VERSION 5.7 ;
  NOWIREEXTENSIONATPIN ON ;
  DIVIDERCHAR "/" ;
  BUSBITCHARS "[]" ;
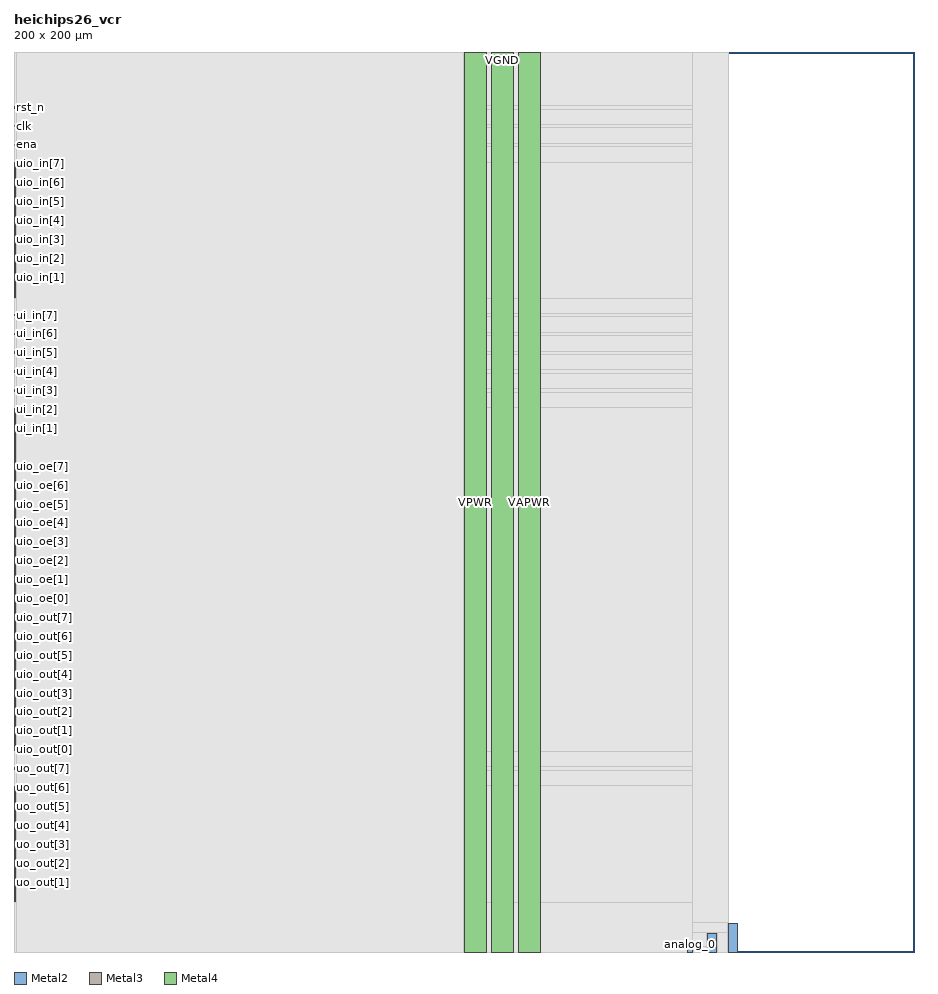
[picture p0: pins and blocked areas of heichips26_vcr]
MACRO heichips26_vcr
  CLASS BLOCK ;
  FOREIGN heichips26_vcr ;
  ORIGIN 0.000 0.000 ;
  SIZE 200.000 BY 200.000 ;
  PIN analog_0
    ANTENNADIFFAREA 86.099998 ;
    PORT
      LAYER Metal2 ;
        RECT 149.740 0.000 150.740 1.000 ;
    END
  END analog_0
  PIN analog_1
    ANTENNADIFFAREA 57.399998 ;
    PORT
      LAYER Metal2 ;
        RECT 154.040 0.000 156.040 4.170 ;
    END
  END analog_1
  PIN analog_2
    ANTENNADIFFAREA 57.399998 ;
    PORT
      LAYER Metal2 ;
        RECT 158.840 0.000 160.840 6.410 ;
    END
  END analog_2
  PIN clk
    PORT
      LAYER Metal3 ;
        RECT 0.000 183.340 0.400 183.740 ;
    END
  END clk
  PIN ena
    PORT
      LAYER Metal3 ;
        RECT 0.000 179.140 0.400 179.540 ;
    END
  END ena
  PIN rst_n
    PORT
      LAYER Metal3 ;
        RECT 0.000 187.540 0.400 187.940 ;
    END
  END rst_n
  PIN ui_in[0]
    ANTENNADIFFAREA 1.166200 ;
    PORT
      LAYER Metal3 ;
        RECT 0.000 44.740 0.400 120.740 ;
    END
  END ui_in[0]
  PIN ui_in[1]
    PORT
      LAYER Metal3 ;
        RECT 0.000 116.140 0.400 116.540 ;
    END
  END ui_in[1]
  PIN ui_in[2]
    PORT
      LAYER Metal3 ;
        RECT 0.000 120.340 0.400 120.740 ;
    END
  END ui_in[2]
  PIN ui_in[3]
    ANTENNAGATEAREA 9.900000 ;
    PORT
      LAYER Metal3 ;
        RECT 0.000 124.540 2.550 124.940 ;
    END
  END ui_in[3]
  PIN ui_in[4]
    ANTENNAGATEAREA 9.900000 ;
    PORT
      LAYER Metal3 ;
        RECT 0.000 128.740 0.400 129.140 ;
    END
  END ui_in[4]
  PIN ui_in[5]
    ANTENNAGATEAREA 9.900000 ;
    PORT
      LAYER Metal3 ;
        RECT 0.000 132.940 0.400 133.340 ;
    END
  END ui_in[5]
  PIN ui_in[6]
    ANTENNAGATEAREA 9.900000 ;
    PORT
      LAYER Metal3 ;
        RECT 0.000 137.140 0.400 137.540 ;
    END
  END ui_in[6]
  PIN ui_in[7]
    ANTENNAGATEAREA 9.900000 ;
    PORT
      LAYER Metal3 ;
        RECT 0.000 141.340 0.400 141.740 ;
    END
  END ui_in[7]
  PIN uio_in[0]
    ANTENNADIFFAREA 1.166200 ;
    PORT
      LAYER Metal3 ;
        RECT 0.000 145.540 0.400 175.340 ;
    END
  END uio_in[0]
  PIN uio_in[1]
    PORT
      LAYER Metal3 ;
        RECT 0.000 149.740 0.400 150.140 ;
    END
  END uio_in[1]
  PIN uio_in[2]
    PORT
      LAYER Metal3 ;
        RECT 0.000 153.940 0.400 154.340 ;
    END
  END uio_in[2]
  PIN uio_in[3]
    PORT
      LAYER Metal3 ;
        RECT 0.000 158.140 0.400 158.540 ;
    END
  END uio_in[3]
  PIN uio_in[4]
    PORT
      LAYER Metal3 ;
        RECT 0.000 162.340 0.400 162.740 ;
    END
  END uio_in[4]
  PIN uio_in[5]
    PORT
      LAYER Metal3 ;
        RECT 0.000 166.540 0.400 166.940 ;
    END
  END uio_in[5]
  PIN uio_in[6]
    PORT
      LAYER Metal3 ;
        RECT 0.000 170.740 0.400 171.140 ;
    END
  END uio_in[6]
  PIN uio_in[7]
    PORT
      LAYER Metal3 ;
        RECT 0.000 174.940 0.400 175.340 ;
    END
  END uio_in[7]
  PIN uio_oe[0]
    PORT
      LAYER Metal3 ;
        RECT 0.000 78.340 0.400 78.740 ;
    END
  END uio_oe[0]
  PIN uio_oe[1]
    PORT
      LAYER Metal3 ;
        RECT 0.000 82.540 0.400 82.940 ;
    END
  END uio_oe[1]
  PIN uio_oe[2]
    PORT
      LAYER Metal3 ;
        RECT 0.000 86.740 0.400 87.140 ;
    END
  END uio_oe[2]
  PIN uio_oe[3]
    PORT
      LAYER Metal3 ;
        RECT 0.000 90.940 0.400 91.340 ;
    END
  END uio_oe[3]
  PIN uio_oe[4]
    PORT
      LAYER Metal3 ;
        RECT 0.000 95.140 0.400 95.540 ;
    END
  END uio_oe[4]
  PIN uio_oe[5]
    PORT
      LAYER Metal3 ;
        RECT 0.000 99.340 0.400 99.740 ;
    END
  END uio_oe[5]
  PIN uio_oe[6]
    PORT
      LAYER Metal3 ;
        RECT 0.000 103.540 0.400 103.940 ;
    END
  END uio_oe[6]
  PIN uio_oe[7]
    PORT
      LAYER Metal3 ;
        RECT 0.000 107.740 0.400 108.140 ;
    END
  END uio_oe[7]
  PIN uio_out[0]
    PORT
      LAYER Metal3 ;
        RECT 0.000 44.740 0.400 45.140 ;
    END
  END uio_out[0]
  PIN uio_out[1]
    PORT
      LAYER Metal3 ;
        RECT 0.000 48.940 0.400 49.340 ;
    END
  END uio_out[1]
  PIN uio_out[2]
    PORT
      LAYER Metal3 ;
        RECT 0.000 53.140 0.400 53.540 ;
    END
  END uio_out[2]
  PIN uio_out[3]
    PORT
      LAYER Metal3 ;
        RECT 0.000 57.340 0.400 57.740 ;
    END
  END uio_out[3]
  PIN uio_out[4]
    PORT
      LAYER Metal3 ;
        RECT 0.000 61.540 0.400 61.940 ;
    END
  END uio_out[4]
  PIN uio_out[5]
    PORT
      LAYER Metal3 ;
        RECT 0.000 65.740 0.400 66.140 ;
    END
  END uio_out[5]
  PIN uio_out[6]
    PORT
      LAYER Metal3 ;
        RECT 0.000 69.940 0.400 70.340 ;
    END
  END uio_out[6]
  PIN uio_out[7]
    PORT
      LAYER Metal3 ;
        RECT 0.000 74.140 0.400 74.540 ;
    END
  END uio_out[7]
  PIN uo_out[0]
    ANTENNADIFFAREA 1.166200 ;
    PORT
      LAYER Metal3 ;
        RECT 0.000 11.140 0.400 36.740 ;
    END
  END uo_out[0]
  PIN uo_out[1]
    PORT
      LAYER Metal3 ;
        RECT 0.000 15.340 0.400 15.740 ;
    END
  END uo_out[1]
  PIN uo_out[2]
    PORT
      LAYER Metal3 ;
        RECT 0.000 19.540 0.400 19.940 ;
    END
  END uo_out[2]
  PIN uo_out[3]
    PORT
      LAYER Metal3 ;
        RECT 0.000 23.740 0.400 24.140 ;
    END
  END uo_out[3]
  PIN uo_out[4]
    PORT
      LAYER Metal3 ;
        RECT 0.000 27.940 0.400 28.340 ;
    END
  END uo_out[4]
  PIN uo_out[5]
    PORT
      LAYER Metal3 ;
        RECT 0.000 32.140 0.400 32.540 ;
    END
  END uo_out[5]
  PIN uo_out[6]
    PORT
      LAYER Metal3 ;
        RECT 0.000 36.340 0.400 36.740 ;
    END
  END uo_out[6]
  PIN uo_out[7]
    ANTENNADIFFAREA 9.880000 ;
    PORT
      LAYER Metal3 ;
        RECT 0.000 40.540 0.400 40.940 ;
    END
  END uo_out[7]
  PIN VAPWR
    USE POWER ;
    ANTENNADIFFAREA 987.272156 ;
    PORT
      LAYER Metal4 ;
        RECT 112.000 0.000 117.000 200.000 ;
    END
  END VAPWR
  PIN VGND
    USE GROUND ;
    ANTENNADIFFAREA 744.113403 ;
    PORT
      LAYER Metal4 ;
        RECT 106.000 0.000 111.000 200.000 ;
    END
  END VGND
  PIN VPWR
    USE POWER ;
    ANTENNAGATEAREA 4.630500 ;
    ANTENNADIFFAREA 25.619799 ;
    PORT
      LAYER Metal4 ;
        RECT 100.000 0.000 105.000 200.000 ;
    END
  END VPWR
  OBS
      LAYER GatPoly ;
        RECT 0.620 7.520 111.520 198.560 ;
      LAYER Metal1 ;
        RECT 0.000 7.410 112.615 200.000 ;
      LAYER Metal2 ;
        RECT 0.000 6.620 158.840 200.000 ;
        RECT 0.000 4.380 158.630 6.620 ;
        RECT 0.000 1.210 153.830 4.380 ;
        RECT 0.000 0.000 149.530 1.210 ;
        RECT 150.950 0.000 153.830 1.210 ;
        RECT 156.250 0.000 158.630 4.380 ;
      LAYER Metal3 ;
        RECT 0.000 188.150 150.750 200.000 ;
        RECT 0.610 187.330 150.750 188.150 ;
        RECT 0.000 183.950 150.750 187.330 ;
        RECT 0.610 183.130 150.750 183.950 ;
        RECT 0.000 179.750 150.750 183.130 ;
        RECT 0.610 178.930 150.750 179.750 ;
        RECT 0.000 175.550 150.750 178.930 ;
        RECT 0.610 145.330 150.750 175.550 ;
        RECT 0.000 141.950 150.750 145.330 ;
        RECT 0.000 141.740 0.100 141.950 ;
        RECT 0.610 141.130 150.750 141.950 ;
        RECT 0.000 137.750 150.750 141.130 ;
        RECT 0.000 137.540 0.100 137.750 ;
        RECT 0.610 136.930 150.750 137.750 ;
        RECT 0.000 133.550 150.750 136.930 ;
        RECT 0.000 133.340 0.100 133.550 ;
        RECT 0.610 132.730 150.750 133.550 ;
        RECT 0.000 129.350 150.750 132.730 ;
        RECT 0.000 129.140 0.100 129.350 ;
        RECT 0.610 128.530 150.750 129.350 ;
        RECT 0.000 125.150 150.750 128.530 ;
        RECT 2.760 124.330 150.750 125.150 ;
        RECT 0.000 120.950 150.750 124.330 ;
        RECT 0.610 44.530 150.750 120.950 ;
        RECT 0.000 41.150 150.750 44.530 ;
        RECT 0.000 40.940 0.100 41.150 ;
        RECT 0.610 40.330 150.750 41.150 ;
        RECT 0.000 36.950 150.750 40.330 ;
        RECT 0.610 10.930 150.750 36.950 ;
        RECT 0.000 0.000 150.750 10.930 ;
      LAYER Metal4 ;
        RECT 0.620 0.000 99.790 200.000 ;
  END
END heichips26_vcr
END LIBRARY

